(* Logix 5000 Rung export; software revision 20.05; part 2 of 2 *)

ADD_ON_INSTRUCTION AOI1734MBS_CONFIG_08   (* revision 1.10, vendor ProSoft Technology Inc. *)
// Configuration file used for non-AOP applications
// Revision note:
// V1.7 - Resend command if stale
// V1.8 - Function Code 4 Swap for revision 1.15 or lower
// V1.9 - Built AOI in RSlogix v16
// v1.10 - Removed retransmission logic
// Help:
// Previous Version 1.8 was not able to open up in v16 Rslogix 5000 project.
// Built it back again to support v16 and up.
VAR_IN_OUT
   Connection_Input : SINT[34]; {required}
   Connection_Output : SINT[26]; {required}
   Connection_Configuration : INT[198]; {required}
   MBS : ILX34MBSModuleDef; {required}
   MBS_Config : ILX34MBSConfig; {required}
END_VAR

ROUTINE Logic   (* ladder *)
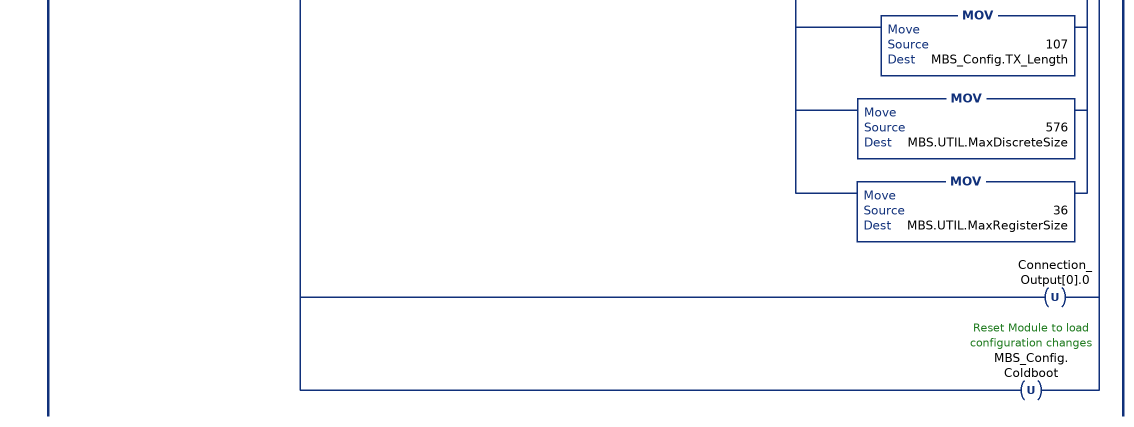
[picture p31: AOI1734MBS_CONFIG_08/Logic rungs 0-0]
   0: [XIC(MBS_Config.Coldboot) [CPT(Connection_Configuration[3],MBS_Config.Serial_COM+(MBS_Config.Protocol*256)) ,CPT(Connection_Configuration[4],MBS_Config.RX_Length+(MBS_Config.Baud_Rate*256)) ,CPT(Connection_Configuration[5],MBS_Config.Type+(MBS_Config.TX_Length*256)) ,EQU(MBS_Config.Type,0) COP(MBS_Config.Timeout,Connection_Configuration[6],2) ,EQU(MBS_Config.Type,1) [MOV(MBS_Config.Slave_ID,Connection_Configuration[8]) ,MOV(MBS_Config.Reserved02,Connection_Configuration[9]) MOV(MBS_Config.Output_Coil_Count_0X,Connection_Configuration[10]) ,MOV(MBS_Config.Reserved01,Connection_Configuration[11]) MOV(MBS_Config.Input_Status_Count_1X,Connection_Configuration[12]) ,MOV(MBS_Config.Reserved03,Connection_Configuration[13]) MOV(MBS_Config.Input_Register_Count_3X,Connection_Configuration[14]) ,MOV(MBS_Config.Reserved04,Connection_Configuration[15]) MOV(MBS_Config.Holding_Register_Count_4X,Connection_Configuration[16]) ] ,NEQ(Connection_Input[0],-1) OTL(Connection_Output[0].0) [ADD(1,MBS.UTIL.TXID_Previous,MBS.UTIL.TXID_Previous) ,MOV(MBS.UTIL.TXID_Previous,Connection_Output[2]) ,FLL(0,Connection_Output[3],2) ] ] ,EQU(Connection_Input[0],-1) [CPT(Connection_Configuration[3],MBS_Config.Serial_COM+(MBS_Config.Protocol*256)) ,CPT(Connection_Configuration[4],MBS_Config.RX_Length+(MBS_Config.Baud_Rate*256)) ,CPT(Connection_Configuration[5],MBS_Config.Type+(MBS_Config.TX_Length*256)) ,EQU(MBS_Config.Type,0) COP(MBS_Config.Timeout,Connection_Configuration[6],2) ,EQU(MBS_Config.Type,1) [MOV(MBS_Config.Slave_ID,Connection_Configuration[8]) ,MOV(MBS_Config.Reserved02,Connection_Configuration[9]) MOV(MBS_Config.Output_Coil_Count_0X,Connection_Configuration[10]) ,MOV(MBS_Config.Reserved01,Connection_Configuration[11]) MOV(MBS_Config.Input_Status_Count_1X,Connection_Configuration[12]) ,MOV(MBS_Config.Reserved03,Connection_Configuration[13]) MOV(MBS_Config.Input_Register_Count_3X,Connection_Configuration[14]) ,MOV(MBS_Config.Reserved04,Connection_Configuration[15]) MOV(MBS_Config.Holding_Register_Count_4X,Connection_Configuration[16]) ] ,SIZE(Connection_Input,0,MBS.UTIL.InArraySize) SIZE(Connection_Output,0,MBS.UTIL.OutArraySize) CPT(MBS.UTIL.WaitTimer.PRE,MBS_Config.Timeout * 10 + 10000) ,EQU(MBS.UTIL.InArraySize,34) EQU(MBS.UTIL.OutArraySize,26) [MOV(102,MBS_Config.RX_Length) ,MOV(101,MBS_Config.TX_Length) ,MOV(128,MBS.UTIL.MaxDiscreteSize) ,MOV(8,MBS.UTIL.MaxRegisterSize) ] ,EQU(MBS.UTIL.InArraySize,66) EQU(MBS.UTIL.OutArraySize,58) [MOV(106,MBS_Config.RX_Length) ,MOV(105,MBS_Config.TX_Length) ,MOV(384,MBS.UTIL.MaxDiscreteSize) ,MOV(24,MBS.UTIL.MaxRegisterSize) ] ,EQU(MBS.UTIL.InArraySize,90) EQU(MBS.UTIL.OutArraySize,82) [MOV(108,MBS_Config.RX_Length) ,MOV(107,MBS_Config.TX_Length) ,MOV(576,MBS.UTIL.MaxDiscreteSize) ,MOV(36,MBS.UTIL.MaxRegisterSize) ] ,OTU(Connection_Output[0].0) ,OTU(MBS_Config.Coldboot) ] ];
END_ROUTINE
END_ADD_ON_INSTRUCTION

VAR_GLOBAL   (* controller tags *)
   MBS : ILX34MBSModuleDef;
   Local:2:O : AB:1734_MODULE_SINT_26Bytes:O:0;
   MBS_AOI_08 : AOI1734MBS_08;
   Local:2:C : AB:1734_MODULE:C:0 := (Reserved := 1);
   Local:2:I : AB:1734_MODULE_SINT_34Bytes:I:0;
   MBS_Config : ILX34MBSConfig := (Baud_Rate := 4, Serial_COM := 3, Protocol := 1, RX_Length := 108, TX_Length := 107, Timeout := 300, Input_Status_Count_1X := 576, Output_Coil_Count_0X := 576, Input_Register_Count_3X := 500, Holding_Register_Count_4X := 500);
   MBSConfig_AOI_08 : AOI1734MBS_CONFIG_08;
END_VAR

PROGRAM MainProgram

ROUTINE MainRoutine   (* ladder *)
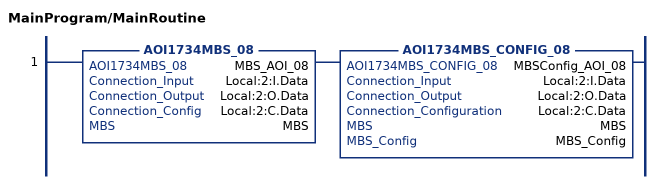
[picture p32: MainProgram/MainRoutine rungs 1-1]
   1: AOI1734MBS_08(MBS_AOI_08,Local:2:I.Data,Local:2:O.Data,Local:2:C.Data,MBS)AOI1734MBS_CONFIG_08(MBSConfig_AOI_08,Local:2:I.Data,Local:2:O.Data,Local:2:C.Data,MBS,MBS_Config);
END_ROUTINE
END_PROGRAM
